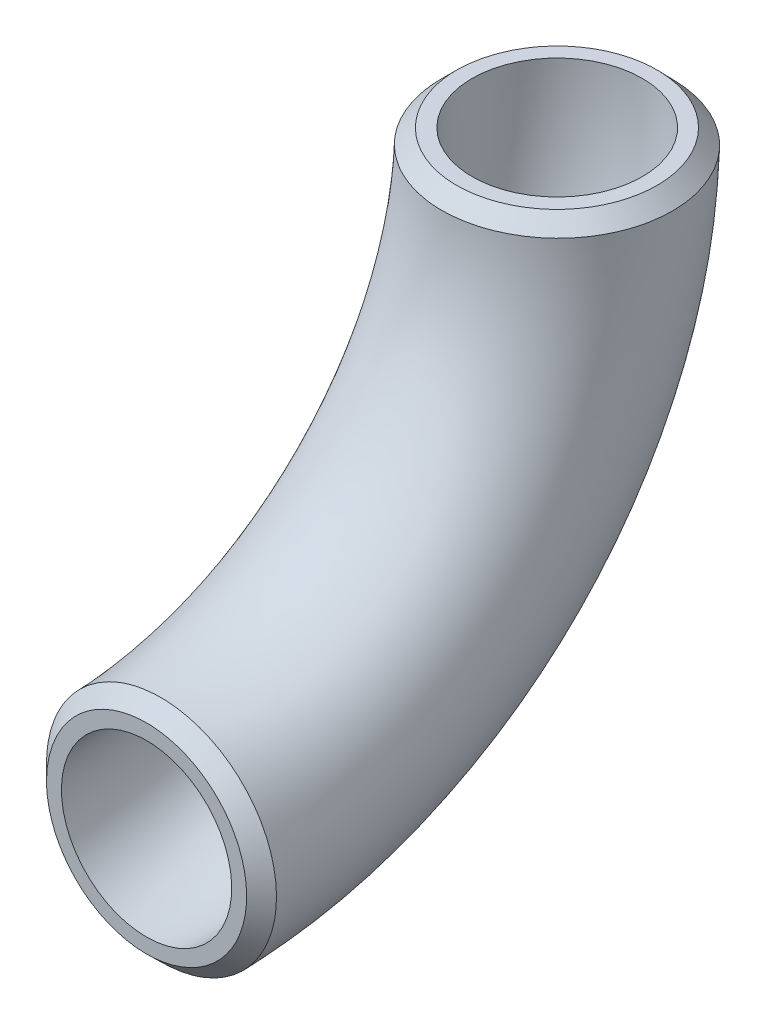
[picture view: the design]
ISO-10303-21;
HEADER;
FILE_DESCRIPTION(('STEP AP214'),'2;1');
FILE_NAME('part.step','',(''),(''),'','','');
FILE_SCHEMA(('AUTOMOTIVE_DESIGN { 1 0 10303 214 1 1 1 1 }'));
ENDSEC;
DATA;
#1=APPLICATION_CONTEXT('core data for automotive mechanical design processes');
#2=APPLICATION_PROTOCOL_DEFINITION('international standard','automotive_design',2000,#1);
#3=PRODUCT_CONTEXT('',#1,'mechanical');
#4=PRODUCT('Part','Part','',(#3));
#5=PRODUCT_RELATED_PRODUCT_CATEGORY('part','',(#4));
#6=PRODUCT_DEFINITION_FORMATION('','',#4);
#7=PRODUCT_DEFINITION_CONTEXT('part definition',#1,'design');
#8=PRODUCT_DEFINITION('design','',#6,#7);
#9=PRODUCT_DEFINITION_SHAPE('','',#8);
#10=(LENGTH_UNIT() NAMED_UNIT(*) SI_UNIT(.MILLI.,.METRE.));
#11=(NAMED_UNIT(*) PLANE_ANGLE_UNIT() SI_UNIT($,.RADIAN.));
#12=(NAMED_UNIT(*) SI_UNIT($,.STERADIAN.) SOLID_ANGLE_UNIT());
#13=UNCERTAINTY_MEASURE_WITH_UNIT(LENGTH_MEASURE(1.E-05),#10,'distance_accuracy_value','');
#14=(GEOMETRIC_REPRESENTATION_CONTEXT(3) GLOBAL_UNCERTAINTY_ASSIGNED_CONTEXT((#13)) GLOBAL_UNIT_ASSIGNED_CONTEXT((#10,
#11,#12)) REPRESENTATION_CONTEXT('',''));
#15=CARTESIAN_POINT('',(0.,0.,0.));
#16=DIRECTION('',(0.,0.,1.));
#17=DIRECTION('',(1.,0.,0.));
#18=AXIS2_PLACEMENT_3D('',#15,#16,#17);
#19=CARTESIAN_POINT('',(0.,38.1,0.));
#20=DIRECTION('',(-1.,0.,0.));
#21=DIRECTION('',(0.,0.,1.));
#22=AXIS2_PLACEMENT_3D('',#19,#20,#21);
#23=TOROIDAL_SURFACE('',#22,38.1,7.8994);
#24=CARTESIAN_POINT('',(0.,38.1,-38.1));
#25=DIRECTION('',(0.,1.,0.));
#26=DIRECTION('',(-1.,0.,0.));
#27=AXIS2_PLACEMENT_3D('',#24,#25,#26);
#28=CIRCLE('',#27,7.8994);
#29=CARTESIAN_POINT('',(0.,38.1,-45.9994));
#30=VERTEX_POINT('',#29);
#31=EDGE_CURVE('E63',#30,#30,#28,.T.);
#32=CARTESIAN_POINT('',(0.,0.,0.));
#33=DIRECTION('',(0.,0.,-1.));
#34=DIRECTION('',(-1.,0.,0.));
#35=AXIS2_PLACEMENT_3D('',#32,#33,#34);
#36=CIRCLE('',#35,7.8994);
#37=CARTESIAN_POINT('',(0.,-7.89939999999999,0.));
#38=VERTEX_POINT('',#37);
#39=EDGE_CURVE('E68',#38,#38,#36,.T.);
#40=CARTESIAN_POINT('',(0.,38.1,0.));
#41=DIRECTION('',(-1.,0.,0.));
#42=DIRECTION('',(0.,0.,1.));
#43=AXIS2_PLACEMENT_3D('',#40,#41,#42);
#44=CIRCLE('',#43,45.9994);
#45=EDGE_CURVE('',#30,#38,#44,.T.);
#46=ORIENTED_EDGE('',*,*,#31,.T.);
#47=ORIENTED_EDGE('',*,*,#39,.F.);
#48=ORIENTED_EDGE('',*,*,#45,.T.);
#49=ORIENTED_EDGE('',*,*,#45,.F.);
#50=EDGE_LOOP('',(#46,#48,#47,#49));
#51=FACE_BOUND('',#50,.T.);
#52=ADVANCED_FACE('F36',(#51),#23,.F.);
#53=CARTESIAN_POINT('',(0.,38.1,0.));
#54=DIRECTION('',(-1.,0.,0.));
#55=DIRECTION('',(0.,0.,1.));
#56=AXIS2_PLACEMENT_3D('',#53,#54,#55);
#57=TOROIDAL_SURFACE('',#56,38.1,10.668);
#58=CARTESIAN_POINT('',(-10.6679608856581,36.7155638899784,-38.1037461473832));
#59=CARTESIAN_POINT('',(-10.6712198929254,36.7221295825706,-36.7049100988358));
#60=CARTESIAN_POINT('',(-10.4015135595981,36.7293412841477,-35.3151911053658));
#61=CARTESIAN_POINT('',(-9.33458055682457,36.744176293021,-32.7239405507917));
#62=CARTESIAN_POINT('',(-8.55617914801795,36.751665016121,-31.5463033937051));
#63=CARTESIAN_POINT('',(-6.57364641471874,36.7653747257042,-29.5511046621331));
#64=CARTESIAN_POINT('',(-5.40077360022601,36.7713347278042,-28.7650983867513));
#65=CARTESIAN_POINT('',(-2.8156955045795,36.7798319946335,-27.6823186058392));
#66=CARTESIAN_POINT('',(-1.4271327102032,36.7821687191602,-27.4045568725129));
#67=CARTESIAN_POINT('',(2.7701344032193,36.7822619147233,-27.391983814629));
#68=CARTESIAN_POINT('',(5.53729471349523,36.7724846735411,-28.5309414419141));
#69=CARTESIAN_POINT('',(8.51098501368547,36.7520035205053,-31.4898224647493));
#70=CARTESIAN_POINT('',(9.30350059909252,36.7445339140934,-32.6642943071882));
#71=CARTESIAN_POINT('',(10.380604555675,36.7297030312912,-35.2493265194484));
#72=CARTESIAN_POINT('',(10.661885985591,36.7224962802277,-36.6351928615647));
#73=CARTESIAN_POINT('',(10.6739938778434,36.7092415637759,-39.4428599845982));
#74=CARTESIAN_POINT('',(10.3930080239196,36.7032472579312,-40.8531458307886));
#75=CARTESIAN_POINT('',(9.33746880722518,36.6931186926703,-43.4201557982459));
#76=CARTESIAN_POINT('',(8.54915437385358,36.6888252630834,-44.6107330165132));
#77=CARTESIAN_POINT('',(6.57653247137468,36.6820330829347,-46.5932710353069));
#78=CARTESIAN_POINT('',(5.40287707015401,36.6794966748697,-47.3853089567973));
#79=CARTESIAN_POINT('',(2.81321808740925,36.6761119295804,-48.4631194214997));
#80=CARTESIAN_POINT('',(1.42697162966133,36.6752664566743,-48.7441498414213));
#81=CARTESIAN_POINT('',(-1.37999031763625,36.6752499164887,-48.750166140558));
#82=CARTESIAN_POINT('',(-2.76843811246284,36.6760766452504,-48.4747502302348));
#83=CARTESIAN_POINT('',(-5.35894367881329,36.6794164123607,-47.4104731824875));
#84=CARTESIAN_POINT('',(-6.53759644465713,36.6819400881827,-46.6232179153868));
#85=CARTESIAN_POINT('',(-9.5100469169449,36.692052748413,-43.6629605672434));
#86=CARTESIAN_POINT('',(-10.6614428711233,36.7024325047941,-40.9014182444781));
#87=CARTESIAN_POINT('',(-10.6679608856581,36.7155638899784,-38.1037461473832));
#88=B_SPLINE_CURVE_WITH_KNOTS('',3,(#58,#59,#60,#61,#62,#63,#64,#65,#66,#67,#68,#69,#70,#71,#72,
#73,#74,#75,#76,#77,#78,#79,#80,#81,#82,#83,#84,#85,#86,#87),.UNSPECIFIED.,.T.,.F.,(4,2,2,2,2,2,
2,2,2,2,2,2,2,2,4),(-0.0570412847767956,-0.0534123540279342,-0.0497834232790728,
-0.0461544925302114,-0.04252556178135,-0.0352677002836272,-0.0316387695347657,
-0.0280098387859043,-0.0243809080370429,-0.0207519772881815,-0.0171230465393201,
-0.0134941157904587,-0.00986518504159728,-0.00623625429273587,0.00102160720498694),.UNSPECIFIED.);
#89=CARTESIAN_POINT('',(-10.6679608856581,36.7155638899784,-38.1037461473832));
#90=VERTEX_POINT('',#89);
#91=EDGE_CURVE('E48',#90,#90,#88,.F.);
#92=ORIENTED_EDGE('',*,*,#91,.T.);
#93=EDGE_LOOP('',(#92));
#94=FACE_BOUND('',#93,.T.);
#95=CARTESIAN_POINT('',(-10.6679608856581,-0.00374614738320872,-1.38443611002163));
#96=CARTESIAN_POINT('',(-10.66732328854,-0.203506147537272,-1.38537376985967));
#97=CARTESIAN_POINT('',(-10.661132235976,-0.403250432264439,-1.38629902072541));
#98=CARTESIAN_POINT('',(-10.6376664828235,-0.801713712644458,-1.38812133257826));
#99=CARTESIAN_POINT('',(-10.6204124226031,-1.00043392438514,-1.38901844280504));
#100=CARTESIAN_POINT('',(-10.5748651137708,-1.39639773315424,-1.39078368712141));
#101=CARTESIAN_POINT('',(-10.5465833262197,-1.59364264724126,-1.39165185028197));
#102=CARTESIAN_POINT('',(-10.4790357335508,-1.9862044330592,-1.39335844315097));
#103=CARTESIAN_POINT('',(-10.4397720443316,-2.18152166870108,-1.39419687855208));
#104=CARTESIAN_POINT('',(-10.350309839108,-2.5697767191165,-1.39584322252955));
#105=CARTESIAN_POINT('',(-10.3001038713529,-2.76271281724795,-1.39665110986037));
#106=CARTESIAN_POINT('',(-10.1888202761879,-3.14576047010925,-1.39823569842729));
#107=CARTESIAN_POINT('',(-10.1277253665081,-3.33586700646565,-1.39901234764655));
#108=CARTESIAN_POINT('',(-9.99467817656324,-3.7127920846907,-1.40053332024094));
#109=CARTESIAN_POINT('',(-9.92269836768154,-3.89960090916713,-1.40127755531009));
#110=CARTESIAN_POINT('',(-9.76834197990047,-4.26891332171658,-1.40273190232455));
#111=CARTESIAN_POINT('',(-9.68596330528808,-4.45141603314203,-1.40344200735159));
#112=CARTESIAN_POINT('',(-9.51138206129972,-4.8111504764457,-1.40482708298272));
#113=CARTESIAN_POINT('',(-9.41920213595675,-4.98839319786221,-1.40550212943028));
#114=CARTESIAN_POINT('',(-9.22521964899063,-5.3372123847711,-1.406816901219));
#115=CARTESIAN_POINT('',(-9.12343059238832,-5.50879635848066,-1.40745667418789));
#116=CARTESIAN_POINT('',(-8.91047883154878,-5.8459247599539,-1.40870120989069));
#117=CARTESIAN_POINT('',(-8.79932087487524,-6.01147218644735,-1.40930599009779));
#118=CARTESIAN_POINT('',(-8.56786754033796,-6.3361501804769,-1.41048070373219));
#119=CARTESIAN_POINT('',(-8.44756859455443,-6.49527820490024,-1.4110506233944));
#120=CARTESIAN_POINT('',(-8.19806998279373,-6.8067400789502,-1.41215587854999));
#121=CARTESIAN_POINT('',(-8.06885883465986,-6.95906473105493,-1.41269116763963));
#122=CARTESIAN_POINT('',(-7.80178062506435,-7.25655270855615,-1.41372718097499));
#123=CARTESIAN_POINT('',(-7.66389458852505,-7.40169900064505,-1.41422782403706));
#124=CARTESIAN_POINT('',(-7.38011740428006,-7.68398961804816,-1.41519394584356));
#125=CARTESIAN_POINT('',(-7.23422501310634,-7.82113269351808,-1.41565941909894));
#126=CARTESIAN_POINT('',(-6.9352305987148,-8.08667535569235,-1.41655459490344));
#127=CARTESIAN_POINT('',(-6.78214414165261,-8.21509247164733,-1.41698436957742));
#128=CARTESIAN_POINT('',(-6.46920580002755,-8.4629592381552,-1.41780835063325));
#129=CARTESIAN_POINT('',(-6.30936311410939,-8.58242050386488,-1.41820260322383));
#130=CARTESIAN_POINT('',(-5.98334548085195,-8.81214052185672,-1.41895597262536));
#131=CARTESIAN_POINT('',(-5.81717452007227,-8.92240493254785,-1.41931511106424));
#132=CARTESIAN_POINT('',(-5.47893671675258,-9.13350324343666,-1.41999862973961));
#133=CARTESIAN_POINT('',(-5.30686961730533,-9.23433673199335,-1.42032300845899));
#134=CARTESIAN_POINT('',(-4.95726732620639,-9.426328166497,-1.42093736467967));
#135=CARTESIAN_POINT('',(-4.77972846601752,-9.51747943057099,-1.42122731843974));
#136=CARTESIAN_POINT('',(-4.4196358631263,-9.68992299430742,-1.42177331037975));
#137=CARTESIAN_POINT('',(-4.2370758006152,-9.77120210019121,-1.42202930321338));
#138=CARTESIAN_POINT('',(-3.86765060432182,-9.92334300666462,-1.42250689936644));
#139=CARTESIAN_POINT('',(-3.68078526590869,-9.99420431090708,-1.42272850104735));
#140=CARTESIAN_POINT('',(-3.30355822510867,-10.1250795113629,-1.42313658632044));
#141=CARTESIAN_POINT('',(-3.11320122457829,-10.1851069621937,-1.42332311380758));
#142=CARTESIAN_POINT('',(-2.72955402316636,-10.2943012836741,-1.42366141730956));
#143=CARTESIAN_POINT('',(-2.53626613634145,-10.3434762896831,-1.42381321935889));
#144=CARTESIAN_POINT('',(-2.1472952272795,-10.430887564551,-1.42408229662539));
#145=CARTESIAN_POINT('',(-1.95161295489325,-10.4691271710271,-1.42419958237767));
#146=CARTESIAN_POINT('',(-1.55839708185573,-10.5346128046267,-1.42439989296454));
#147=CARTESIAN_POINT('',(-1.36086329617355,-10.561857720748,-1.42448291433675));
#148=CARTESIAN_POINT('',(-0.964485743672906,-10.6052672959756,-1.42461492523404));
#149=CARTESIAN_POINT('',(-0.765641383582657,-10.6214265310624,-1.42466389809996));
#150=CARTESIAN_POINT('',(-0.367184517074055,-10.6426799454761,-1.42472813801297));
#151=CARTESIAN_POINT('',(-0.16757148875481,-10.6477643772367,-1.42474337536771));
#152=CARTESIAN_POINT('',(0.231601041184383,-10.6465072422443,-1.42474011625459));
#153=CARTESIAN_POINT('',(0.431160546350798,-10.6401670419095,-1.42472162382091));
#154=CARTESIAN_POINT('',(0.829374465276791,-10.6159637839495,-1.42465046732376));
#155=CARTESIAN_POINT('',(1.02802959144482,-10.598112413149,-1.42459783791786));
#156=CARTESIAN_POINT('',(1.42388728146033,-10.5511983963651,-1.42445841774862));
#157=CARTESIAN_POINT('',(1.62109064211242,-10.5221424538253,-1.42437164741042));
#158=CARTESIAN_POINT('',(2.01349497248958,-10.4530278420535,-1.42416385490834));
#159=CARTESIAN_POINT('',(2.20869654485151,-10.4129725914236,-1.42404284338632));
#160=CARTESIAN_POINT('',(2.59654839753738,-10.3220933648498,-1.4237664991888));
#161=CARTESIAN_POINT('',(2.78919899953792,-10.2712707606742,-1.42361117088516));
#162=CARTESIAN_POINT('',(3.17139981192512,-10.1590823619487,-1.4232661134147));
#163=CARTESIAN_POINT('',(3.36095008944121,-10.097716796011,-1.4230763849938));
#164=CARTESIAN_POINT('',(3.73640112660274,-9.9646690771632,-1.42266244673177));
#165=CARTESIAN_POINT('',(3.92230176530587,-9.8929865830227,-1.42243823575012));
#166=CARTESIAN_POINT('',(4.28990424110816,-9.73953050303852,-1.42195524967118));
#167=CARTESIAN_POINT('',(4.47160581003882,-9.65775627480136,-1.42169647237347));
#168=CARTESIAN_POINT('',(4.83026091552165,-9.48434222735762,-1.421144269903));
#169=CARTESIAN_POINT('',(5.00721399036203,-9.39270145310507,-1.42085084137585));
#170=CARTESIAN_POINT('',(5.35582246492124,-9.19977933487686,-1.42022925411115));
#171=CARTESIAN_POINT('',(5.52747701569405,-9.09849645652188,-1.41990108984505));
#172=CARTESIAN_POINT('',(5.86494064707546,-8.88651714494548,-1.41920994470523));
#173=CARTESIAN_POINT('',(6.03074808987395,-8.77581810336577,-1.41884695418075));
#174=CARTESIAN_POINT('',(6.35596394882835,-8.54522756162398,-1.41808609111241));
#175=CARTESIAN_POINT('',(6.51536926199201,-8.42533168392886,-1.41768820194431));
#176=CARTESIAN_POINT('',(6.82725106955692,-8.17659318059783,-1.41685740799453));
#177=CARTESIAN_POINT('',(6.97972199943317,-8.0477435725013,-1.41642447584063));
#178=CARTESIAN_POINT('',(7.27712012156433,-7.78125475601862,-1.41552373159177));
#179=CARTESIAN_POINT('',(7.42203778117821,-7.64360490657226,-1.41505587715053));
#180=CARTESIAN_POINT('',(7.70374376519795,-7.36030392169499,-1.4140854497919));
#181=CARTESIAN_POINT('',(7.84053414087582,-7.21465482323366,-1.41358288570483));
#182=CARTESIAN_POINT('',(8.1056210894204,-6.91625520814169,-1.41254290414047));
#183=CARTESIAN_POINT('',(8.23393133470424,-6.76351683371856,-1.41200554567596));
#184=CARTESIAN_POINT('',(8.48169476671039,-6.45124554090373,-1.41089598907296));
#185=CARTESIAN_POINT('',(8.60115604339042,-6.29171904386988,-1.4103238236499));
#186=CARTESIAN_POINT('',(8.83094898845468,-5.96626470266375,-1.40914438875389));
#187=CARTESIAN_POINT('',(8.94128232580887,-5.80033803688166,-1.40853712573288));
#188=CARTESIAN_POINT('',(9.15252017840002,-5.46245129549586,-1.40728731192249));
#189=CARTESIAN_POINT('',(9.25341911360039,-5.29048773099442,-1.40664474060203));
#190=CARTESIAN_POINT('',(9.44550934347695,-4.94090640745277,-1.40532408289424));
#191=CARTESIAN_POINT('',(9.53668684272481,-4.76328106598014,-1.40464594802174));
#192=CARTESIAN_POINT('',(9.7090053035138,-4.40273199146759,-1.40325403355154));
#193=CARTESIAN_POINT('',(9.79012302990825,-4.2197971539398,-1.40254017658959));
#194=CARTESIAN_POINT('',(9.94192654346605,-3.84968028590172,-1.40107877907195));
#195=CARTESIAN_POINT('',(10.0126136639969,-3.66249880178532,-1.40033124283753));
#196=CARTESIAN_POINT('',(10.1433015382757,-3.28494678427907,-1.39880472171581));
#197=CARTESIAN_POINT('',(10.2033276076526,-3.09458501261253,-1.39802581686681));
#198=CARTESIAN_POINT('',(10.3125797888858,-2.7110573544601,-1.39643691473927));
#199=CARTESIAN_POINT('',(10.3618200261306,-2.51789549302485,-1.39562695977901));
#200=CARTESIAN_POINT('',(10.4494353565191,-2.12917082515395,-1.39397620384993));
#201=CARTESIAN_POINT('',(10.4878129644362,-1.93360858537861,-1.3931354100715));
#202=CARTESIAN_POINT('',(10.5536323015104,-1.54047983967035,-1.39142327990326));
#203=CARTESIAN_POINT('',(10.5810646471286,-1.34291176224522,-1.39055191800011));
#204=CARTESIAN_POINT('',(10.6248983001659,-0.94616786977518,-1.38877882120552));
#205=CARTESIAN_POINT('',(10.6412780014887,-0.746989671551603,-1.38787703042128));
#206=CARTESIAN_POINT('',(10.6630161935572,-0.347421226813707,-1.38604370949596));
#207=CARTESIAN_POINT('',(10.6683408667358,-0.147029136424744,-1.3851120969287));
#208=CARTESIAN_POINT('',(10.6675839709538,0.254109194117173,-1.38322022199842));
#209=CARTESIAN_POINT('',(10.6614813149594,0.454855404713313,-1.38225990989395));
#210=CARTESIAN_POINT('',(10.6377444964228,0.855602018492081,-1.38031473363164));
#211=CARTESIAN_POINT('',(10.620113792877,1.0556026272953,-1.37932987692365));
#212=CARTESIAN_POINT('',(10.5736326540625,1.45414029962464,-1.37733973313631));
#213=CARTESIAN_POINT('',(10.5447906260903,1.65267834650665,-1.37633446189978));
#214=CARTESIAN_POINT('',(10.4760905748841,2.04756967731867,-1.37430716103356));
#215=CARTESIAN_POINT('',(10.4362470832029,2.24392549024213,-1.37328515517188));
#216=CARTESIAN_POINT('',(10.3457748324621,2.63373095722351,-1.37122817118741));
#217=CARTESIAN_POINT('',(10.2951673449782,2.82718554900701,-1.37019322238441));
#218=CARTESIAN_POINT('',(10.1833911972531,3.21046629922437,-1.36811413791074));
#219=CARTESIAN_POINT('',(10.1222507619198,3.40030068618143,-1.367070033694));
#220=CARTESIAN_POINT('',(9.98962850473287,3.77561696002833,-1.36497632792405));
#221=CARTESIAN_POINT('',(9.91818166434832,3.96111119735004,-1.36392675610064));
#222=CARTESIAN_POINT('',(9.76494798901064,4.32760160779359,-1.36182290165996));
#223=CARTESIAN_POINT('',(9.68316958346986,4.50860130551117,-1.36076862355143));
#224=CARTESIAN_POINT('',(9.50945665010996,4.86609248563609,-1.35865784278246));
#225=CARTESIAN_POINT('',(9.41750264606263,5.0425744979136,-1.35760133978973));
#226=CARTESIAN_POINT('',(9.22376797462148,5.39043523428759,-1.35549134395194));
#227=CARTESIAN_POINT('',(9.1219715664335,5.56180519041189,-1.35443785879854));
#228=CARTESIAN_POINT('',(8.90888826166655,5.89884823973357,-1.35233925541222));
#229=CARTESIAN_POINT('',(8.79758932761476,6.06451372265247,-1.35129414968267));
#230=CARTESIAN_POINT('',(8.56583164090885,6.38954966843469,-1.34921759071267));
#231=CARTESIAN_POINT('',(8.44536418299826,6.54891392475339,-1.34818615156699));
#232=CARTESIAN_POINT('',(8.19561572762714,6.86076329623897,-1.34614239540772));
#233=CARTESIAN_POINT('',(8.06632872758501,7.01324360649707,-1.34513009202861));
#234=CARTESIAN_POINT('',(7.79923262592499,7.31068784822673,-1.34312942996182));
#235=CARTESIAN_POINT('',(7.66141931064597,7.45564799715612,-1.34214108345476));
#236=CARTESIAN_POINT('',(7.37796902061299,7.73741528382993,-1.34019694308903));
#237=CARTESIAN_POINT('',(7.23233982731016,7.87423025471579,-1.33924111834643));
#238=CARTESIAN_POINT('',(6.93398430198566,8.13932099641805,-1.33737076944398));
#239=CARTESIAN_POINT('',(6.78127145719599,8.26761194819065,-1.33645617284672));
#240=CARTESIAN_POINT('',(6.46905879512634,8.51533151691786,-1.33467286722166));
#241=CARTESIAN_POINT('',(6.30956571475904,8.63476862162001,-1.33380411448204));
#242=CARTESIAN_POINT('',(5.98415583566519,8.86451382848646,-1.33211771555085));
#243=CARTESIAN_POINT('',(5.81823962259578,8.9748227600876,-1.33130006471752));
#244=CARTESIAN_POINT('',(5.48033051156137,9.18602824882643,-1.3297208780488));
#245=CARTESIAN_POINT('',(5.30833273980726,9.28691700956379,-1.32895938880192));
#246=CARTESIAN_POINT('',(4.95861528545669,9.47901447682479,-1.32749767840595));
#247=CARTESIAN_POINT('',(4.78088599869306,9.57020570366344,-1.32679756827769));
#248=CARTESIAN_POINT('',(4.42004122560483,9.74259996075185,-1.32546332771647));
#249=CARTESIAN_POINT('',(4.23691215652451,9.82377456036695,-1.32482938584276));
#250=CARTESIAN_POINT('',(3.86633633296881,9.97570633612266,-1.32363589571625));
#251=CARTESIAN_POINT('',(3.67888859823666,10.0464611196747,-1.32307636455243));
#252=CARTESIAN_POINT('',(3.30079522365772,10.1772433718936,-1.32203792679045));
#253=CARTESIAN_POINT('',(3.1101584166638,10.2372963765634,-1.3215588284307));
#254=CARTESIAN_POINT('',(2.72611675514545,10.3465556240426,-1.32068327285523));
#255=CARTESIAN_POINT('',(2.53271660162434,10.3957783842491,-1.32028668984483));
#256=CARTESIAN_POINT('',(2.14359303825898,10.4832985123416,-1.31957859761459));
#257=CARTESIAN_POINT('',(1.94787123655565,10.5216030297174,-1.31926703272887));
#258=CARTESIAN_POINT('',(1.55454381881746,10.5871992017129,-1.31873127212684));
#259=CARTESIAN_POINT('',(1.3569377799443,10.6144883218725,-1.31850709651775));
#260=CARTESIAN_POINT('',(0.960281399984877,10.6579623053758,-1.31814851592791));
#261=CARTESIAN_POINT('',(0.761229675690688,10.6741345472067,-1.31801421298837));
#262=CARTESIAN_POINT('',(0.362120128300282,10.6953096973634,-1.31783745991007));
#263=CARTESIAN_POINT('',(0.162061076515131,10.7002894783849,-1.31779519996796));
#264=CARTESIAN_POINT('',(-0.238064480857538,10.6989171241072,-1.31780573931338));
#265=CARTESIAN_POINT('',(-0.438130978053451,10.6925624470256,-1.317858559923));
#266=CARTESIAN_POINT('',(-0.837224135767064,10.6685390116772,-1.31805762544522));
#267=CARTESIAN_POINT('',(-1.03625201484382,10.6508904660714,-1.31820370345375));
#268=CARTESIAN_POINT('',(-1.43276991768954,10.6044569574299,-1.31858600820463));
#269=CARTESIAN_POINT('',(-1.63026145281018,10.5756848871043,-1.31882213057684));
#270=CARTESIAN_POINT('',(-2.02320808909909,10.50715281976,-1.31938155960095));
#271=CARTESIAN_POINT('',(-2.21866431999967,10.4673992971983,-1.31970481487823));
#272=CARTESIAN_POINT('',(-2.60704442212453,10.377063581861,-1.32043549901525));
#273=CARTESIAN_POINT('',(-2.79996845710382,10.3264820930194,-1.32084292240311));
#274=CARTESIAN_POINT('',(-3.1827819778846,10.2146305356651,-1.32173886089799));
#275=CARTESIAN_POINT('',(-3.37267011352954,10.1533558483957,-1.32222741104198));
#276=CARTESIAN_POINT('',(-3.74893535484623,10.020319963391,-1.32328289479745));
#277=CARTESIAN_POINT('',(-3.93530905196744,9.94854912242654,-1.32384990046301));
#278=CARTESIAN_POINT('',(-4.3037181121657,9.79459874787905,-1.32505735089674));
#279=CARTESIAN_POINT('',(-4.48575333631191,9.71241888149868,-1.32569779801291));
#280=CARTESIAN_POINT('',(-4.84468633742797,9.53790045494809,-1.32704504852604));
#281=CARTESIAN_POINT('',(-5.02158852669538,9.44557096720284,-1.3277517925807));
#282=CARTESIAN_POINT('',(-5.36982498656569,9.25115361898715,-1.32922663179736));
#283=CARTESIAN_POINT('',(-5.54116207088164,9.14907079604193,-1.32999469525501));
#284=CARTESIAN_POINT('',(-5.87780931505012,8.93548346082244,-1.33158676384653));
#285=CARTESIAN_POINT('',(-6.0431206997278,8.82398087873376,-1.33241075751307));
#286=CARTESIAN_POINT('',(-6.36726937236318,8.59191083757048,-1.33410950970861));
#287=CARTESIAN_POINT('',(-6.52610623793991,8.47134278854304,-1.33498427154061));
#288=CARTESIAN_POINT('',(-6.83683968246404,8.22147650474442,-1.33677890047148));
#289=CARTESIAN_POINT('',(-6.98873403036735,8.09217549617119,-1.33769878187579));
#290=CARTESIAN_POINT('',(-7.28518068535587,7.82524291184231,-1.33957972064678));
#291=CARTESIAN_POINT('',(-7.42972866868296,7.68760653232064,-1.34054080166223));
#292=CARTESIAN_POINT('',(-7.71068298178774,7.4043241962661,-1.34249267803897));
#293=CARTESIAN_POINT('',(-7.84709141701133,7.25868032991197,-1.34348346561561));
#294=CARTESIAN_POINT('',(-8.1111541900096,6.95990551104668,-1.34548459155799));
#295=CARTESIAN_POINT('',(-8.23881652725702,6.80678162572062,-1.3464949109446));
#296=CARTESIAN_POINT('',(-8.48521236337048,6.49364564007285,-1.34853255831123));
#297=CARTESIAN_POINT('',(-8.60395050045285,6.33363718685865,-1.34955987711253));
#298=CARTESIAN_POINT('',(-8.83225614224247,6.00726718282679,-1.35162725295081));
#299=CARTESIAN_POINT('',(-8.94182590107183,5.84090720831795,-1.35266730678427));
#300=CARTESIAN_POINT('',(-9.15156966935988,5.50238468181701,-1.35475635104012));
#301=CARTESIAN_POINT('',(-9.25174434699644,5.3302225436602,-1.35580534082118));
#302=CARTESIAN_POINT('',(-9.4424672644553,4.98064092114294,-1.35790833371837));
#303=CARTESIAN_POINT('',(-9.53301522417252,4.80322128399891,-1.35896233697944));
#304=CARTESIAN_POINT('',(-9.70425461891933,4.44367054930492,-1.36107146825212));
#305=CARTESIAN_POINT('',(-9.78494525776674,4.26153907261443,-1.36212659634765));
#306=CARTESIAN_POINT('',(-9.93623913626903,3.89310993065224,-1.36423408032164));
#307=CARTESIAN_POINT('',(-10.0068412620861,3.70681180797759,-1.36528643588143));
#308=CARTESIAN_POINT('',(-10.1377271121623,3.33059460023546,-1.36738448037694));
#309=CARTESIAN_POINT('',(-10.1980093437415,3.14067499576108,-1.36843016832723));
#310=CARTESIAN_POINT('',(-10.308024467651,2.75776006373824,-1.37051098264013));
#311=CARTESIAN_POINT('',(-10.3577551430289,2.56476409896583,-1.3715461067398));
#312=CARTESIAN_POINT('',(-10.4464364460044,2.17624160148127,-1.37360189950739));
#313=CARTESIAN_POINT('',(-10.4853834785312,1.98071424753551,-1.37462256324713));
#314=CARTESIAN_POINT('',(-10.5522679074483,1.58767472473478,-1.37664554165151));
#315=CARTESIAN_POINT('',(-10.58019934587,1.39016154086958,-1.37764784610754));
#316=CARTESIAN_POINT('',(-10.6248222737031,0.993694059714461,-1.37963021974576));
#317=CARTESIAN_POINT('',(-10.6415041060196,0.794738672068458,-1.38061026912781));
#318=CARTESIAN_POINT('',(-10.6634052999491,0.395937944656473,-1.38254423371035));
#319=CARTESIAN_POINT('',(-10.6686096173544,0.196091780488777,-1.38349811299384));
#320=CARTESIAN_POINT('',(-10.6679608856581,-0.00374614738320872,-1.38443611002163));
#321=B_SPLINE_CURVE_WITH_KNOTS('',3,(#95,#96,#97,#98,#99,#100,#101,#102,#103,#104,#105,#106,
#107,#108,#109,#110,#111,#112,#113,#114,#115,#116,#117,#118,#119,#120,#121,#122,#123,#124,#125,
#126,#127,#128,#129,#130,#131,#132,#133,#134,#135,#136,#137,#138,#139,#140,#141,#142,#143,#144,
#145,#146,#147,#148,#149,#150,#151,#152,#153,#154,#155,#156,#157,#158,#159,#160,#161,#162,#163,
#164,#165,#166,#167,#168,#169,#170,#171,#172,#173,#174,#175,#176,#177,#178,#179,#180,#181,#182,
#183,#184,#185,#186,#187,#188,#189,#190,#191,#192,#193,#194,#195,#196,#197,#198,#199,#200,#201,
#202,#203,#204,#205,#206,#207,#208,#209,#210,#211,#212,#213,#214,#215,#216,#217,#218,#219,#220,
#221,#222,#223,#224,#225,#226,#227,#228,#229,#230,#231,#232,#233,#234,#235,#236,#237,#238,#239,
#240,#241,#242,#243,#244,#245,#246,#247,#248,#249,#250,#251,#252,#253,#254,#255,#256,#257,#258,
#259,#260,#261,#262,#263,#264,#265,#266,#267,#268,#269,#270,#271,#272,#273,#274,#275,#276,#277,
#278,#279,#280,#281,#282,#283,#284,#285,#286,#287,#288,#289,#290,#291,#292,#293,#294,#295,#296,
#297,#298,#299,#300,#301,#302,#303,#304,#305,#306,#307,#308,#309,#310,#311,#312,#313,#314,#315,
#316,#317,#318,#319,#320),.UNSPECIFIED.,.F.,.F.,(4,2,2,2,2,2,2,2,2,2,2,2,2,2,2,2,2,2,2,2,2,2,2,
2,2,2,2,2,2,2,2,2,2,2,2,2,2,2,2,2,2,2,2,2,2,2,2,2,2,2,2,2,2,2,2,2,2,2,2,2,2,2,2,2,2,2,2,2,2,2,2,
2,2,2,2,2,2,2,2,2,2,2,2,2,2,2,2,2,2,2,2,2,2,2,2,2,2,2,2,2,2,2,2,2,2,2,2,2,2,2,2,2,4),(0.,
0.599215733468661,1.1973167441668,1.79479780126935,2.39216382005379,2.98993792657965,
3.58866937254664,4.1889411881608,4.78933417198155,5.38836901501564,5.98657414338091,
6.58447794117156,7.18261632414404,7.78154026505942,8.38182316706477,8.98219956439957,
9.58133187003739,10.1796731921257,10.7776436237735,11.3756401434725,11.9740467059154,
12.5732444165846,13.1724706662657,13.7709419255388,14.3689630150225,14.9668013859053,
15.5647001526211,16.1628912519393,16.76160864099,17.3602544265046,17.9582933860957,
18.5559751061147,19.1534712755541,19.7508913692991,20.3482985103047,20.9457254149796,
21.5431903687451,22.1407132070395,22.738331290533,23.3361154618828,23.9341859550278,
24.5327281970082,25.1320083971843,25.7311366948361,26.3292741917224,26.926857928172,
27.5243321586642,28.1221575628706,28.7208203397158,29.3208410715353,29.9207850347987,
30.519284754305,31.1169959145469,31.7145685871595,32.3126524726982,32.9119021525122,
33.5129822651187,34.1151726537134,34.7171824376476,35.3187416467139,35.9195100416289,
36.5191020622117,37.1171116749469,37.7131373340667,38.3086798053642,38.9053825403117,
39.5030558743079,40.1014978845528,40.7005153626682,41.299944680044,41.8996726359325,
42.4988141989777,43.0968584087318,43.6943216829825,44.2917306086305,44.8896296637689,
45.4885887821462,46.089210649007,46.6899702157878,47.2892765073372,47.8876623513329,
48.4856554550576,49.0837860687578,49.6825946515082,50.2826394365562,50.8828188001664,
51.4819270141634,52.0803429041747,52.6784067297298,53.2764316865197,53.8747155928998,
54.4735526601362,55.0724088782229,55.6707340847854,56.268751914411,56.8666475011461,
57.4645820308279,58.0627073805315,58.6611807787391,59.2594986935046,59.8572618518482,
60.4547121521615,61.0520151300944,61.6492755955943,62.246553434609,62.843879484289,
63.4412714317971,64.0387497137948,64.6363534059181,65.2341560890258,65.8322816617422,
66.4309200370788,67.0303426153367),.UNSPECIFIED.);
#322=CARTESIAN_POINT('',(-10.6679608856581,-0.00374614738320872,-1.38443611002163));
#323=VERTEX_POINT('',#322);
#324=EDGE_CURVE('E53',#323,#323,#321,.F.);
#325=ORIENTED_EDGE('',*,*,#324,.T.);
#326=EDGE_LOOP('',(#325));
#327=FACE_BOUND('',#326,.T.);
#328=ADVANCED_FACE('F90',(#94,#327),#57,.T.);
#329=CARTESIAN_POINT('',(0.,38.1,-38.1));
#330=DIRECTION('',(0.,1.,0.));
#331=DIRECTION('',(-1.,0.,0.));
#332=AXIS2_PLACEMENT_3D('',#329,#330,#331);
#333=PLANE('',#332);
#334=CARTESIAN_POINT('',(-9.28366596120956,38.1,-38.1));
#335=CARTESIAN_POINT('',(-9.28326468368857,38.1,-38.2738063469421));
#336=CARTESIAN_POINT('',(-9.2777801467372,38.1,-38.4475916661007));
#337=CARTESIAN_POINT('',(-9.25683286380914,38.1,-38.7943622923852));
#338=CARTESIAN_POINT('',(-9.24138150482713,38.1,-38.9673482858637));
#339=CARTESIAN_POINT('',(-9.20070164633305,38.1,-39.3120385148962));
#340=CARTESIAN_POINT('',(-9.1754801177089,38.1,-39.4837435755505));
#341=CARTESIAN_POINT('',(-9.11546451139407,38.1,-39.825397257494));
#342=CARTESIAN_POINT('',(-9.0806744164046,38.1,-39.9953465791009));
#343=CARTESIAN_POINT('',(-9.00172345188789,38.1,-40.3330124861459));
#344=CARTESIAN_POINT('',(-8.95756469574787,38.1,-40.5007295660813));
#345=CARTESIAN_POINT('',(-8.86007746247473,38.1,-40.8334551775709));
#346=CARTESIAN_POINT('',(-8.80675004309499,38.1,-40.9984640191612));
#347=CARTESIAN_POINT('',(-8.69112564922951,38.1,-41.3252971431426));
#348=CARTESIAN_POINT('',(-8.62882920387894,38.1,-41.4871216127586));
#349=CARTESIAN_POINT('',(-8.49546641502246,38.1,-41.8071098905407));
#350=CARTESIAN_POINT('',(-8.42440033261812,38.1,-41.9652738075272));
#351=CARTESIAN_POINT('',(-8.2736977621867,38.1,-42.277464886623));
#352=CARTESIAN_POINT('',(-8.1940612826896,38.1,-42.4314920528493));
#353=CARTESIAN_POINT('',(-8.02641705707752,38.1,-42.7349332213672));
#354=CARTESIAN_POINT('',(-7.93840885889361,38.1,-42.8843469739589));
#355=CARTESIAN_POINT('',(-7.75422183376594,38.1,-43.1780862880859));
#356=CARTESIAN_POINT('',(-7.65804168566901,38.1,-43.3224110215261));
#357=CARTESIAN_POINT('',(-7.45770698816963,38.1,-43.6054929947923));
#358=CARTESIAN_POINT('',(-7.35354966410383,38.1,-43.7442482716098));
#359=CARTESIAN_POINT('',(-7.13747540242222,38.1,-44.0157298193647));
#360=CARTESIAN_POINT('',(-7.02555352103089,38.1,-44.1484521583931));
#361=CARTESIAN_POINT('',(-6.7940984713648,38.1,-44.4073428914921));
#362=CARTESIAN_POINT('',(-6.67455730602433,38.1,-44.5335041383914));
#363=CARTESIAN_POINT('',(-6.4284642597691,38.1,-44.7787896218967));
#364=CARTESIAN_POINT('',(-6.30191223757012,38.1,-44.8979137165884));
#365=CARTESIAN_POINT('',(-6.04252937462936,38.1,-45.1288236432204));
#366=CARTESIAN_POINT('',(-5.90970547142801,38.1,-45.2406172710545));
#367=CARTESIAN_POINT('',(-5.6380920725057,38.1,-45.456534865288));
#368=CARTESIAN_POINT('',(-5.49930621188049,38.1,-45.5606634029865));
#369=CARTESIAN_POINT('',(-5.21614711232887,38.1,-45.7609871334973));
#370=CARTESIAN_POINT('',(-5.07177453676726,38.1,-45.8571832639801));
#371=CARTESIAN_POINT('',(-4.77780082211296,38.1,-46.0413573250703));
#372=CARTESIAN_POINT('',(-4.62819768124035,38.1,-46.1293320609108));
#373=CARTESIAN_POINT('',(-4.32413203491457,38.1,-46.2967976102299));
#374=CARTESIAN_POINT('',(-4.16966512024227,38.1,-46.3762804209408));
#375=CARTESIAN_POINT('',(-3.85621709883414,38.1,-46.5264439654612));
#376=CARTESIAN_POINT('',(-3.69722939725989,38.1,-46.597110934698));
#377=CARTESIAN_POINT('',(-3.37553391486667,38.1,-46.7293698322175));
#378=CARTESIAN_POINT('',(-3.2128262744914,38.1,-46.7909621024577));
#379=CARTESIAN_POINT('',(-2.88450360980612,38.1,-46.9049307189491));
#380=CARTESIAN_POINT('',(-2.71889358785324,38.1,-46.9573214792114));
#381=CARTESIAN_POINT('',(-2.38514911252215,38.1,-47.0527419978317));
#382=CARTESIAN_POINT('',(-2.21701691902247,38.1,-47.0957796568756));
#383=CARTESIAN_POINT('',(-1.87863113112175,38.1,-47.1724017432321));
#384=CARTESIAN_POINT('',(-1.70837776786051,38.1,-47.2059871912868));
#385=CARTESIAN_POINT('',(-1.36614634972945,38.1,-47.2635986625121));
#386=CARTESIAN_POINT('',(-1.19416724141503,38.1,-47.287618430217));
#387=CARTESIAN_POINT('',(-0.848881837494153,38.1,-47.325997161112));
#388=CARTESIAN_POINT('',(-0.675573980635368,38.1,-47.3403420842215));
#389=CARTESIAN_POINT('',(-0.328027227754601,38.1,-47.3592667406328));
#390=CARTESIAN_POINT('',(-0.153787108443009,38.1,-47.3638240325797));
#391=CARTESIAN_POINT('',(0.194657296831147,38.1,-47.3630804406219));
#392=CARTESIAN_POINT('',(0.368861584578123,38.1,-47.3577803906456));
#393=CARTESIAN_POINT('',(0.716278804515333,38.1,-47.3373779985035));
#394=CARTESIAN_POINT('',(0.889493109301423,38.1,-47.3222990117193));
#395=CARTESIAN_POINT('',(1.23455362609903,38.1,-47.2824492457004));
#396=CARTESIAN_POINT('',(1.40640143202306,38.1,-47.257692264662));
#397=CARTESIAN_POINT('',(1.7483527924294,38.1,-47.1985978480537));
#398=CARTESIAN_POINT('',(1.91845717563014,38.1,-47.16426520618));
#399=CARTESIAN_POINT('',(2.25654793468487,38.1,-47.0861331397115));
#400=CARTESIAN_POINT('',(2.42453345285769,38.1,-47.0423300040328));
#401=CARTESIAN_POINT('',(2.75800829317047,38.1,-46.9453569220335));
#402=CARTESIAN_POINT('',(2.92349418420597,38.1,-46.8921751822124));
#403=CARTESIAN_POINT('',(3.25161231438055,38.1,-46.776594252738));
#404=CARTESIAN_POINT('',(3.41423771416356,38.1,-46.7141756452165));
#405=CARTESIAN_POINT('',(3.7357218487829,38.1,-46.5802839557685));
#406=CARTESIAN_POINT('',(3.89458057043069,38.1,-46.5088108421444));
#407=CARTESIAN_POINT('',(4.20763164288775,38.1,-46.3570919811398));
#408=CARTESIAN_POINT('',(4.36183326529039,38.1,-46.2768653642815));
#409=CARTESIAN_POINT('',(4.66525445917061,38.1,-46.1079599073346));
#410=CARTESIAN_POINT('',(4.81448063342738,38.1,-46.019292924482));
#411=CARTESIAN_POINT('',(5.10761330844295,38.1,-45.8337758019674));
#412=CARTESIAN_POINT('',(5.25152337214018,38.1,-45.7369312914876));
#413=CARTESIAN_POINT('',(5.53369523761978,38.1,-45.5353433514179));
#414=CARTESIAN_POINT('',(5.67195716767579,38.1,-45.4306001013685));
#415=CARTESIAN_POINT('',(5.94249214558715,38.1,-45.2134836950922));
#416=CARTESIAN_POINT('',(6.07476147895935,38.1,-45.1011059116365));
#417=CARTESIAN_POINT('',(6.33301191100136,38.1,-44.8690304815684));
#418=CARTESIAN_POINT('',(6.4589850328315,38.1,-44.7493239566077));
#419=CARTESIAN_POINT('',(6.70408068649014,38.1,-44.5028606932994));
#420=CARTESIAN_POINT('',(6.82319657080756,38.1,-44.3760973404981));
#421=CARTESIAN_POINT('',(7.05405182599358,38.1,-44.1160098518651));
#422=CARTESIAN_POINT('',(7.16579069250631,38.1,-43.982685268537));
#423=CARTESIAN_POINT('',(7.38160623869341,38.1,-43.710043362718));
#424=CARTESIAN_POINT('',(7.48568531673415,38.1,-43.5707279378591));
#425=CARTESIAN_POINT('',(7.68585245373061,38.1,-43.2866325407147));
#426=CARTESIAN_POINT('',(7.78194666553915,38.1,-43.1418569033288));
#427=CARTESIAN_POINT('',(7.96582570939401,38.1,-42.8473797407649));
#428=CARTESIAN_POINT('',(8.05362105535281,38.1,-42.6976847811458));
#429=CARTESIAN_POINT('',(8.22058002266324,38.1,-42.3939053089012));
#430=CARTESIAN_POINT('',(8.29975886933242,38.1,-42.2398291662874));
#431=CARTESIAN_POINT('',(8.4491641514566,38.1,-41.9278237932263));
#432=CARTESIAN_POINT('',(8.51941056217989,38.1,-41.7699041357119));
#433=CARTESIAN_POINT('',(8.65086672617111,38.1,-41.4501657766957));
#434=CARTESIAN_POINT('',(8.71206750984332,38.1,-41.2883433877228));
#435=CARTESIAN_POINT('',(8.82553928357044,38.1,-40.9608880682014));
#436=CARTESIAN_POINT('',(8.8777742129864,38.1,-40.7952426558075));
#437=CARTESIAN_POINT('',(8.97310305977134,38.1,-40.4608100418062));
#438=CARTESIAN_POINT('',(9.01616930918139,38.1,-40.2920149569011));
#439=CARTESIAN_POINT('',(9.09294930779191,38.1,-39.9519538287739));
#440=CARTESIAN_POINT('',(9.12664406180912,38.1,-39.7806834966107));
#441=CARTESIAN_POINT('',(9.18446323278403,38.1,-39.4363432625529));
#442=CARTESIAN_POINT('',(9.20857722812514,38.1,-39.2632716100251));
#443=CARTESIAN_POINT('',(9.24704086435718,38.1,-38.9160018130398));
#444=CARTESIAN_POINT('',(9.26138819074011,38.1,-38.7418034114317));
#445=CARTESIAN_POINT('',(9.2800358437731,38.1,-38.3929520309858));
#446=CARTESIAN_POINT('',(9.28434106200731,38.1,-38.2182993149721));
#447=CARTESIAN_POINT('',(9.28295576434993,38.1,-37.8693842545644));
#448=CARTESIAN_POINT('',(9.27728503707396,38.1,-37.6951218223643));
#449=CARTESIAN_POINT('',(9.25628384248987,38.1,-37.347618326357));
#450=CARTESIAN_POINT('',(9.24097751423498,38.1,-37.1743757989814));
#451=CARTESIAN_POINT('',(9.20073529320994,38.1,-36.8292958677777));
#452=CARTESIAN_POINT('',(9.17581503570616,38.1,-36.6574566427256));
#453=CARTESIAN_POINT('',(9.11646257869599,38.1,-36.3155655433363));
#454=CARTESIAN_POINT('',(9.08203769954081,38.1,-36.1455123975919));
#455=CARTESIAN_POINT('',(9.00377277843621,38.1,-35.8075737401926));
#456=CARTESIAN_POINT('',(8.95993207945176,38.1,-35.6396883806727));
#457=CARTESIAN_POINT('',(8.86292613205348,38.1,-35.306469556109));
#458=CARTESIAN_POINT('',(8.80975247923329,38.1,-35.141138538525));
#459=CARTESIAN_POINT('',(8.69421473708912,38.1,-34.813393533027));
#460=CARTESIAN_POINT('',(8.63183473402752,38.1,-34.6509851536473));
#461=CARTESIAN_POINT('',(8.49801523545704,38.1,-34.3299178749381));
#462=CARTESIAN_POINT('',(8.42657462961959,38.1,-34.1712594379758));
#463=CARTESIAN_POINT('',(8.27490750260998,38.1,-33.8585138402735));
#464=CARTESIAN_POINT('',(8.19469525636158,38.1,-33.7044197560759));
#465=CARTESIAN_POINT('',(8.02580736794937,38.1,-33.4011403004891));
#466=CARTESIAN_POINT('',(7.93714006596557,38.1,-33.2519502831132));
#467=CARTESIAN_POINT('',(7.75161716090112,38.1,-32.958837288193));
#468=CARTESIAN_POINT('',(7.65476490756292,38.1,-32.8149121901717));
#469=CARTESIAN_POINT('',(7.45316325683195,38.1,-32.5326769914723));
#470=CARTESIAN_POINT('',(7.34841290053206,38.1,-32.3943675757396));
#471=CARTESIAN_POINT('',(7.13128401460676,38.1,-32.1237309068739));
#472=CARTESIAN_POINT('',(7.01890072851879,38.1,-31.9914074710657));
#473=CARTESIAN_POINT('',(6.78684360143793,38.1,-31.7330419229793));
#474=CARTESIAN_POINT('',(6.66716163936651,38.1,-31.6070071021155));
#475=CARTESIAN_POINT('',(6.42079118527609,38.1,-31.3619705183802));
#476=CARTESIAN_POINT('',(6.29410260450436,38.1,-31.2429688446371));
#477=CARTESIAN_POINT('',(6.03418797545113,38.1,-31.0126251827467));
#478=CARTESIAN_POINT('',(5.90096907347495,38.1,-30.9012751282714));
#479=CARTESIAN_POINT('',(5.6285276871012,38.1,-30.686374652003));
#480=CARTESIAN_POINT('',(5.48930917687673,38.1,-30.5828191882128));
#481=CARTESIAN_POINT('',(5.20533473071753,38.1,-30.3837185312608));
#482=CARTESIAN_POINT('',(5.06058082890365,38.1,-30.2881704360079));
#483=CARTESIAN_POINT('',(4.7660183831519,38.1,-30.1052773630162));
#484=CARTESIAN_POINT('',(4.61621075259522,38.1,-30.0179309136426));
#485=CARTESIAN_POINT('',(4.31201812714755,38.1,-29.8516397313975));
#486=CARTESIAN_POINT('',(4.15763346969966,38.1,-29.7726943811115));
#487=CARTESIAN_POINT('',(3.84476484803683,38.1,-29.6234032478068));
#488=CARTESIAN_POINT('',(3.6862809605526,38.1,-29.5530573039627));
#489=CARTESIAN_POINT('',(3.3656913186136,38.1,-29.4211636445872));
#490=CARTESIAN_POINT('',(3.20358552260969,38.1,-29.3596160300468));
#491=CARTESIAN_POINT('',(2.87622948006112,38.1,-29.2455176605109));
#492=CARTESIAN_POINT('',(2.71097909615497,38.1,-29.1929672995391));
#493=CARTESIAN_POINT('',(2.37781124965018,38.1,-29.097062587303));
#494=CARTESIAN_POINT('',(2.20989350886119,38.1,-29.0537092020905));
#495=CARTESIAN_POINT('',(1.87186841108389,38.1,-28.9763953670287));
#496=CARTESIAN_POINT('',(1.70176057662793,38.1,-28.9424370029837));
#497=CARTESIAN_POINT('',(1.35983265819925,38.1,-28.8841168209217));
#498=CARTESIAN_POINT('',(1.18801188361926,38.1,-28.8597590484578));
#499=CARTESIAN_POINT('',(0.84313597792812,38.1,-28.8208157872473));
#500=CARTESIAN_POINT('',(0.67008003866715,38.1,-28.8062374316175));
#501=CARTESIAN_POINT('',(0.323209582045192,38.1,-28.787128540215));
#502=CARTESIAN_POINT('',(0.149394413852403,38.1,-28.7826097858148));
#503=CARTESIAN_POINT('',(-0.198185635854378,38.1,-28.7835158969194));
#504=CARTESIAN_POINT('',(-0.371950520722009,38.1,-28.7889397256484));
#505=CARTESIAN_POINT('',(-0.718672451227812,38.1,-28.8094122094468));
#506=CARTESIAN_POINT('',(-0.891630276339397,38.1,-28.8244477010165));
#507=CARTESIAN_POINT('',(-1.23630315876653,38.1,-28.8641669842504));
#508=CARTESIAN_POINT('',(-1.40801906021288,38.1,-28.8888434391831));
#509=CARTESIAN_POINT('',(-1.74977561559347,38.1,-28.9477660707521));
#510=CARTESIAN_POINT('',(-1.91981650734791,38.1,-28.9820108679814));
#511=CARTESIAN_POINT('',(-2.25778915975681,38.1,-29.0600228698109));
#512=CARTESIAN_POINT('',(-2.42571983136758,38.1,-29.103794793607));
#513=CARTESIAN_POINT('',(-2.75904532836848,38.1,-29.2007904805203));
#514=CARTESIAN_POINT('',(-2.92443693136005,38.1,-29.2540253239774));
#515=CARTESIAN_POINT('',(-3.2522346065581,38.1,-29.3699373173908));
#516=CARTESIAN_POINT('',(-3.4146343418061,38.1,-29.4326323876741));
#517=CARTESIAN_POINT('',(-3.73561636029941,38.1,-29.567034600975));
#518=CARTESIAN_POINT('',(-3.89419943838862,38.1,-29.6387398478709));
#519=CARTESIAN_POINT('',(-4.20680534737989,38.1,-29.7906627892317));
#520=CARTESIAN_POINT('',(-4.36083739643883,38.1,-29.8708615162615));
#521=CARTESIAN_POINT('',(-4.66401007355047,38.1,-30.0396405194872));
#522=CARTESIAN_POINT('',(-4.8131560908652,38.1,-30.1282111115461));
#523=CARTESIAN_POINT('',(-5.10625236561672,38.1,-30.3135445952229));
#524=CARTESIAN_POINT('',(-5.25020301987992,38.1,-30.4103068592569));
#525=CARTESIAN_POINT('',(-5.53259842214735,38.1,-30.6118504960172));
#526=CARTESIAN_POINT('',(-5.67103742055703,38.1,-30.7166399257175));
#527=CARTESIAN_POINT('',(-5.94210247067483,38.1,-30.9340608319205));
#528=CARTESIAN_POINT('',(-6.07471542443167,38.1,-31.0467086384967));
#529=CARTESIAN_POINT('',(-6.33382155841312,38.1,-31.279671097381));
#530=CARTESIAN_POINT('',(-6.46029304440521,38.1,-31.4000098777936));
#531=CARTESIAN_POINT('',(-6.7062562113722,38.1,-31.6476181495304));
#532=CARTESIAN_POINT('',(-6.82574796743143,38.1,-31.7748875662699));
#533=CARTESIAN_POINT('',(-7.05697734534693,38.1,-32.0355330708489));
#534=CARTESIAN_POINT('',(-7.16873933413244,38.1,-32.1688875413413));
#535=CARTESIAN_POINT('',(-7.38435419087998,38.1,-32.4413789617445));
#536=CARTESIAN_POINT('',(-7.48822350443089,38.1,-32.5805028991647));
#537=CARTESIAN_POINT('',(-7.6878978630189,38.1,-32.8642106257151));
#538=CARTESIAN_POINT('',(-7.78371097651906,38.1,-33.0087887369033));
#539=CARTESIAN_POINT('',(-7.9671222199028,38.1,-33.3030817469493));
#540=CARTESIAN_POINT('',(-8.05471965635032,38.1,-33.4527970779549));
#541=CARTESIAN_POINT('',(-8.22153367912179,38.1,-33.7570493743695));
#542=CARTESIAN_POINT('',(-8.30074046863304,38.1,-33.9115917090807));
#543=CARTESIAN_POINT('',(-8.45066557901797,38.1,-34.2251590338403));
#544=CARTESIAN_POINT('',(-8.52136480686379,38.1,-34.3841931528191));
#545=CARTESIAN_POINT('',(-8.65375001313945,38.1,-34.7060126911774));
#546=CARTESIAN_POINT('',(-8.71543409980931,38.1,-34.8687988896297));
#547=CARTESIAN_POINT('',(-8.82932669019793,38.1,-35.1973021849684));
#548=CARTESIAN_POINT('',(-8.88155320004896,38.1,-35.3630130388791));
#549=CARTESIAN_POINT('',(-8.97653787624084,38.1,-35.6969128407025));
#550=CARTESIAN_POINT('',(-9.01930717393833,38.1,-35.865098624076));
#551=CARTESIAN_POINT('',(-9.09532503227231,38.1,-36.2035197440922));
#552=CARTESIAN_POINT('',(-9.12857833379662,38.1,-36.373754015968));
#553=CARTESIAN_POINT('',(-9.18552759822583,38.1,-36.7158383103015));
#554=CARTESIAN_POINT('',(-9.20922218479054,38.1,-36.887688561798));
#555=CARTESIAN_POINT('',(-9.24701121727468,38.1,-37.2325733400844));
#556=CARTESIAN_POINT('',(-9.26109833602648,38.1,-37.4056086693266));
#557=CARTESIAN_POINT('',(-9.27963682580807,38.1,-37.752432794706));
#558=CARTESIAN_POINT('',(-9.28407495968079,38.1,-37.9262222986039));
#559=CARTESIAN_POINT('',(-9.28366596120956,38.1,-38.1));
#560=B_SPLINE_CURVE_WITH_KNOTS('',3,(#334,#335,#336,#337,#338,#339,#340,#341,#342,#343,#344,
#345,#346,#347,#348,#349,#350,#351,#352,#353,#354,#355,#356,#357,#358,#359,#360,#361,#362,#363,
#364,#365,#366,#367,#368,#369,#370,#371,#372,#373,#374,#375,#376,#377,#378,#379,#380,#381,#382,
#383,#384,#385,#386,#387,#388,#389,#390,#391,#392,#393,#394,#395,#396,#397,#398,#399,#400,#401,
#402,#403,#404,#405,#406,#407,#408,#409,#410,#411,#412,#413,#414,#415,#416,#417,#418,#419,#420,
#421,#422,#423,#424,#425,#426,#427,#428,#429,#430,#431,#432,#433,#434,#435,#436,#437,#438,#439,
#440,#441,#442,#443,#444,#445,#446,#447,#448,#449,#450,#451,#452,#453,#454,#455,#456,#457,#458,
#459,#460,#461,#462,#463,#464,#465,#466,#467,#468,#469,#470,#471,#472,#473,#474,#475,#476,#477,
#478,#479,#480,#481,#482,#483,#484,#485,#486,#487,#488,#489,#490,#491,#492,#493,#494,#495,#496,
#497,#498,#499,#500,#501,#502,#503,#504,#505,#506,#507,#508,#509,#510,#511,#512,#513,#514,#515,
#516,#517,#518,#519,#520,#521,#522,#523,#524,#525,#526,#527,#528,#529,#530,#531,#532,#533,#534,
#535,#536,#537,#538,#539,#540,#541,#542,#543,#544,#545,#546,#547,#548,#549,#550,#551,#552,#553,
#554,#555,#556,#557,#558,#559),.UNSPECIFIED.,.F.,.F.,(4,2,2,2,2,2,2,2,2,2,2,2,2,2,2,2,2,2,2,2,2,
2,2,2,2,2,2,2,2,2,2,2,2,2,2,2,2,2,2,2,2,2,2,2,2,2,2,2,2,2,2,2,2,2,2,2,2,2,2,2,2,2,2,2,2,2,2,2,2,
2,2,2,2,2,2,2,2,2,2,2,2,2,2,2,2,2,2,2,2,2,2,2,2,2,2,2,2,2,2,2,2,2,2,2,2,2,2,2,2,2,2,2,4),(0.,
0.521332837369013,1.04207110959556,1.56243852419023,2.08258967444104,2.6026236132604,
3.1225975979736,3.64254091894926,4.16246876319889,4.68239608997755,5.2023515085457,
5.72239114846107,6.24261250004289,6.76316817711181,7.28427951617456,7.80540136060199,
8.3259596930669,8.84620501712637,9.36638875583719,9.88677380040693,10.4076450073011,
10.9293195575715,11.4509744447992,11.9718047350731,12.4921933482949,13.0125257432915,
13.5331978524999,14.0546239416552,14.5772443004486,15.0998204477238,15.6211530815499,
16.141745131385,16.662077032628,17.18261320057,17.7038086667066,18.2261157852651,
18.7484247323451,19.2696142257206,19.790082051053,20.3101944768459,20.8302950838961,
21.350713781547,21.8717759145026,22.3933349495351,22.9149296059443,23.4363602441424,
23.957385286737,24.4777411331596,24.9971620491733,25.5154001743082,26.0341487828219,
26.5549372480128,27.0772756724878,27.600665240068,28.1246225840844,28.6487040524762,
29.1725301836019,29.6953184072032,30.2168021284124,30.7374413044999,31.2576806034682,
31.7779562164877,32.2987027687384,32.8203602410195,33.3420817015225,33.8629664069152,
34.3833425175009,34.9035066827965,35.4237341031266,35.9442887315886,36.4654335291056,
36.9865849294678,37.5071782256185,38.0274318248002,38.5474960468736,39.0674667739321,
39.5873992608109,40.1073220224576,40.6272507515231,41.147202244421,41.6672083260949,
42.1873297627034,42.7076701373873,43.2283896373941,43.7497186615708,44.2709933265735,
44.7915556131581,45.3117225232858,45.8318144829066,46.352164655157,46.87312817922,
47.3950912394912,47.9169446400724,48.4376562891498,48.9577728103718,49.4778495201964,
49.9984552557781,50.5201770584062,51.0436246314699,51.5670665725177,52.088775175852,
52.6093650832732,53.1294272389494,53.6495332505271,54.1702399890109,54.692094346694,
55.2140580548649,55.7350173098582,56.2553600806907,56.7754431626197,57.2956011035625,
57.8161553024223,58.337423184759),.UNSPECIFIED.);
#561=CARTESIAN_POINT('',(-9.28366596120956,38.1,-38.1));
#562=VERTEX_POINT('',#561);
#563=EDGE_CURVE('E58',#562,#562,#560,.F.);
#564=ORIENTED_EDGE('',*,*,#563,.T.);
#565=EDGE_LOOP('',(#564));
#566=FACE_BOUND('',#565,.T.);
#567=ORIENTED_EDGE('',*,*,#31,.F.);
#568=EDGE_LOOP('',(#567));
#569=FACE_BOUND('',#568,.T.);
#570=ADVANCED_FACE('F79',(#566,#569),#333,.T.);
#571=CARTESIAN_POINT('',(0.,0.,0.));
#572=DIRECTION('',(0.,0.,-1.));
#573=DIRECTION('',(-1.,0.,0.));
#574=AXIS2_PLACEMENT_3D('',#571,#572,#573);
#575=PLANE('',#574);
#576=CARTESIAN_POINT('',(-9.28366596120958,0.,0.));
#577=CARTESIAN_POINT('',(-9.29152283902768,2.43709941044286,0.));
#578=CARTESIAN_POINT('',(-8.30078094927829,4.84497820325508,0.));
#579=CARTESIAN_POINT('',(-5.73145559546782,7.43480440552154,0.));
#580=CARTESIAN_POINT('',(-4.70785747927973,8.12693984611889,0.));
#581=CARTESIAN_POINT('',(-2.46205270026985,9.06516735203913,0.));
#582=CARTESIAN_POINT('',(-1.25327513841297,9.31283352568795,0.));
#583=CARTESIAN_POINT('',(1.18717312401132,9.32098717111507,0.));
#584=CARTESIAN_POINT('',(2.39528461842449,9.0840792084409,0.));
#585=CARTESIAN_POINT('',(4.65650787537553,8.15705188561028,0.));
#586=CARTESIAN_POINT('',(5.67968863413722,7.47448661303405,0.));
#587=CARTESIAN_POINT('',(7.40803936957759,5.75675939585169,0.));
#588=CARTESIAN_POINT('',(8.0984166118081,4.72549518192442,0.));
#589=CARTESIAN_POINT('',(9.03053857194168,2.4957427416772,0.));
#590=CARTESIAN_POINT('',(9.28179445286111,1.27289519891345,0.));
#591=CARTESIAN_POINT('',(9.28554074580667,-1.17349505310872,0.));
#592=CARTESIAN_POINT('',(9.04865535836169,-2.37919637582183,0.));
#593=CARTESIAN_POINT('',(8.12293432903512,-4.63768193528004,0.));
#594=CARTESIAN_POINT('',(7.44000569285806,-5.66194701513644,0.));
#595=CARTESIAN_POINT('',(4.86458220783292,-8.25438794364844,0.));
#596=CARTESIAN_POINT('',(2.46103620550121,-9.25659443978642,0.));
#597=CARTESIAN_POINT('',(-1.18871180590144,-9.26685210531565,0.));
#598=CARTESIAN_POINT('',(-2.40046672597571,-9.03138050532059,0.));
#599=CARTESIAN_POINT('',(-4.65258259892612,-8.10321244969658,0.));
#600=CARTESIAN_POINT('',(-5.68045025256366,-7.42281834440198,0.));
#601=CARTESIAN_POINT('',(-7.4114413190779,-5.70055721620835,0.));
#602=CARTESIAN_POINT('',(-8.09689313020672,-4.67817521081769,0.));
#603=CARTESIAN_POINT('',(-9.0390138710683,-2.42488815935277,0.));
#604=CARTESIAN_POINT('',(-9.27973752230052,-1.21854970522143,0.));
#605=CARTESIAN_POINT('',(-9.28366596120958,0.,0.));
#606=B_SPLINE_CURVE_WITH_KNOTS('',3,(#576,#577,#578,#579,#580,#581,#582,#583,#584,#585,#586,
#587,#588,#589,#590,#591,#592,#593,#594,#595,#596,#597,#598,#599,#600,#601,#602,#603,#604,#605),
.UNSPECIFIED.,.T.,.F.,(4,2,2,2,2,2,2,2,2,2,2,2,2,2,4),(0.000922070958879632,0.00818004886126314,
0.0118090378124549,0.0154380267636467,0.0190670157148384,0.0226960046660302,0.0263249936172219,
0.0299539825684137,0.0335829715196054,0.0372119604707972,0.0444699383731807,0.0480989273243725,
0.0517279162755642,0.055356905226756,0.0589858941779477),.UNSPECIFIED.);
#607=CARTESIAN_POINT('',(-9.28366596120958,0.,0.));
#608=VERTEX_POINT('',#607);
#609=EDGE_CURVE('E11',#608,#608,#606,.F.);
#610=ORIENTED_EDGE('',*,*,#609,.T.);
#611=EDGE_LOOP('',(#610));
#612=FACE_BOUND('',#611,.T.);
#613=ORIENTED_EDGE('',*,*,#39,.T.);
#614=EDGE_LOOP('',(#613));
#615=FACE_BOUND('',#614,.T.);
#616=ADVANCED_FACE('F89',(#612,#615),#575,.F.);
#617=CARTESIAN_POINT('',(-9.28366596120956,38.1,-38.1));
#618=CARTESIAN_POINT('',(-9.28650207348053,38.1,-36.8824724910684));
#619=CARTESIAN_POINT('',(-9.05179334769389,38.1,-35.6728472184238));
#620=CARTESIAN_POINT('',(-8.12330760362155,38.1,-33.4173249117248));
#621=CARTESIAN_POINT('',(-7.44591304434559,38.1,-32.3922256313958));
#622=CARTESIAN_POINT('',(-5.72063753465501,38.1,-30.6554037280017));
#623=CARTESIAN_POINT('',(-4.69995893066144,38.1,-29.9711522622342));
#624=CARTESIAN_POINT('',(-2.45032549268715,38.1,-29.0285288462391));
#625=CARTESIAN_POINT('',(-1.24194526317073,38.1,-28.7867112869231));
#626=CARTESIAN_POINT('',(2.41067651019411,38.1,-28.7757660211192));
#627=CARTESIAN_POINT('',(4.81876480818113,38.1,-29.7673454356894));
#628=CARTESIAN_POINT('',(7.40658338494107,38.1,-32.3430616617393));
#629=CARTESIAN_POINT('',(8.09626064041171,38.1,-33.3654057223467));
#630=CARTESIAN_POINT('',(9.0335975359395,38.1,-35.6155169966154));
#631=CARTESIAN_POINT('',(9.27837935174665,38.1,-36.8217894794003));
#632=CARTESIAN_POINT('',(9.2889161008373,38.1,-39.2655480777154));
#633=CARTESIAN_POINT('',(9.04439150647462,38.1,-40.4930121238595));
#634=CARTESIAN_POINT('',(8.12582106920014,38.1,-42.7272151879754));
#635=CARTESIAN_POINT('',(7.43979981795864,38.1,-43.7634193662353));
#636=CARTESIAN_POINT('',(5.72314909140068,38.1,-45.4888827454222));
#637=CARTESIAN_POINT('',(4.70178945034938,38.1,-46.1782103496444));
#638=CARTESIAN_POINT('',(2.4481695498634,38.1,-47.1162494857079));
#639=CARTESIAN_POINT('',(1.2418050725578,38.1,-47.3608342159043));
#640=CARTESIAN_POINT('',(-1.2009201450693,38.1,-47.3660702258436));
#641=CARTESIAN_POINT('',(-2.4092003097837,38.1,-47.1263719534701));
#642=CARTESIAN_POINT('',(-4.6635569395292,38.1,-46.2001113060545));
#643=CARTESIAN_POINT('',(-5.68926547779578,38.1,-45.5149460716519));
#644=CARTESIAN_POINT('',(-8.27600511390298,38.1,-42.938544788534));
#645=CARTESIAN_POINT('',(-9.27799373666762,38.1,-40.5350550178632));
#646=CARTESIAN_POINT('',(-9.28366596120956,38.1,-38.1));
#647=CARTESIAN_POINT('',(-10.6679608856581,36.7155638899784,-38.1037461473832));
#648=CARTESIAN_POINT('',(-10.6712198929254,36.7221295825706,-36.7049100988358));
#649=CARTESIAN_POINT('',(-10.4015135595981,36.7293412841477,-35.3151911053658));
#650=CARTESIAN_POINT('',(-9.33458055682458,36.744176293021,-32.7239405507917));
#651=CARTESIAN_POINT('',(-8.55617914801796,36.751665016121,-31.5463033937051));
#652=CARTESIAN_POINT('',(-6.57364641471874,36.7653747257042,-29.5511046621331));
#653=CARTESIAN_POINT('',(-5.40077360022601,36.7713347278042,-28.7650983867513));
#654=CARTESIAN_POINT('',(-2.81569550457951,36.7798319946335,-27.6823186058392));
#655=CARTESIAN_POINT('',(-1.4271327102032,36.7821687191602,-27.4045568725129));
#656=CARTESIAN_POINT('',(2.7701344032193,36.7822619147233,-27.391983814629));
#657=CARTESIAN_POINT('',(5.53729471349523,36.7724846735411,-28.5309414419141));
#658=CARTESIAN_POINT('',(8.51098501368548,36.7520035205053,-31.4898224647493));
#659=CARTESIAN_POINT('',(9.30350059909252,36.7445339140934,-32.6642943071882));
#660=CARTESIAN_POINT('',(10.380604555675,36.7297030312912,-35.2493265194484));
#661=CARTESIAN_POINT('',(10.661885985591,36.7224962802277,-36.6351928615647));
#662=CARTESIAN_POINT('',(10.6739938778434,36.7092415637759,-39.4428599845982));
#663=CARTESIAN_POINT('',(10.3930080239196,36.7032472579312,-40.8531458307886));
#664=CARTESIAN_POINT('',(9.33746880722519,36.6931186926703,-43.4201557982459));
#665=CARTESIAN_POINT('',(8.54915437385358,36.6888252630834,-44.6107330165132));
#666=CARTESIAN_POINT('',(6.57653247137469,36.6820330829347,-46.5932710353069));
#667=CARTESIAN_POINT('',(5.40287707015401,36.6794966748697,-47.3853089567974));
#668=CARTESIAN_POINT('',(2.81321808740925,36.6761119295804,-48.4631194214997));
#669=CARTESIAN_POINT('',(1.42697162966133,36.6752664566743,-48.7441498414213));
#670=CARTESIAN_POINT('',(-1.37999031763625,36.6752499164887,-48.750166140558));
#671=CARTESIAN_POINT('',(-2.76843811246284,36.6760766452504,-48.4747502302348));
#672=CARTESIAN_POINT('',(-5.35894367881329,36.6794164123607,-47.4104731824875));
#673=CARTESIAN_POINT('',(-6.53759644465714,36.6819400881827,-46.6232179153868));
#674=CARTESIAN_POINT('',(-9.5100469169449,36.692052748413,-43.6629605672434));
#675=CARTESIAN_POINT('',(-10.6614428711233,36.7024325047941,-40.9014182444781));
#676=CARTESIAN_POINT('',(-10.6679608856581,36.7155638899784,-38.1037461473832));
#677=B_SPLINE_SURFACE_WITH_KNOTS('',1,3,((#617,#618,#619,#620,#621,#622,#623,#624,#625,#626,
#627,#628,#629,#630,#631,#632,#633,#634,#635,#636,#637,#638,#639,#640,#641,#642,#643,#644,#645,
#646),(#647,#648,#649,#650,#651,#652,#653,#654,#655,#656,#657,#658,#659,#660,#661,#662,#663,
#664,#665,#666,#667,#668,#669,#670,#671,#672,#673,#674,#675,#676)),.UNSPECIFIED.,.F.,.T.,.F.,(2,
2),(4,2,2,2,2,2,2,2,2,2,2,2,2,2,4),(0.,1.),(-0.0570412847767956,-0.0534123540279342,
-0.0497834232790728,-0.0461544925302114,-0.04252556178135,-0.0352677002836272,
-0.0316387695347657,-0.0280098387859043,-0.0243809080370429,-0.0207519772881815,
-0.0171230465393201,-0.0134941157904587,-0.00986518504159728,-0.00623625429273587,
0.00102160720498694),.UNSPECIFIED.);
#678=ORIENTED_EDGE('',*,*,#91,.F.);
#679=EDGE_LOOP('',(#678));
#680=FACE_BOUND('',#679,.T.);
#681=ORIENTED_EDGE('',*,*,#563,.F.);
#682=EDGE_LOOP('',(#681));
#683=FACE_BOUND('',#682,.T.);
#684=ADVANCED_FACE('F96',(#680,#683),#677,.T.);
#685=CARTESIAN_POINT('',(-10.6679608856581,-0.00374614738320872,-1.38443611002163));
#686=CARTESIAN_POINT('',(-10.67698930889,2.79627480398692,-1.37129322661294));
#687=CARTESIAN_POINT('',(-9.53851710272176,5.56255069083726,-1.35520319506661));
#688=CARTESIAN_POINT('',(-6.58607756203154,8.53764509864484,-1.33467370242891));
#689=CARTESIAN_POINT('',(-5.4098499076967,9.33271014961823,-1.3286840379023));
#690=CARTESIAN_POINT('',(-2.82917136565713,10.4104401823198,-1.32022319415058));
#691=CARTESIAN_POINT('',(-1.44015200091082,10.6949202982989,-1.31783596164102));
#692=CARTESIAN_POINT('',(1.36419346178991,10.7042864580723,-1.31776497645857));
#693=CARTESIAN_POINT('',(2.75244744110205,10.4321635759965,-1.3200467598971));
#694=CARTESIAN_POINT('',(5.35084352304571,9.36729990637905,-1.32841865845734));
#695=CARTESIAN_POINT('',(6.52659158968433,8.58323021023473,-1.334356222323));
#696=CARTESIAN_POINT('',(8.51265809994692,6.60997088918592,-1.34798085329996));
#697=CARTESIAN_POINT('',(9.30597804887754,5.42525194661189,-1.35552126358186));
#698=CARTESIAN_POINT('',(10.3770894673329,2.86360947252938,-1.3702275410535));
#699=CARTESIAN_POINT('',(10.6658103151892,1.45870076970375,-1.37754122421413));
#700=CARTESIAN_POINT('',(10.6701152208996,-1.35199084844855,-1.39079284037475));
#701=CARTESIAN_POINT('',(10.3979076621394,-2.73727223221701,-1.39668728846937));
#702=CARTESIAN_POINT('',(9.33415162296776,-5.33218152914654,-1.40693157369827));
#703=CARTESIAN_POINT('',(8.54939094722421,-6.50904120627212,-1.41117219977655));
#704=CARTESIAN_POINT('',(5.58994398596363,-9.48772696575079,-1.42136740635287));
#705=CARTESIAN_POINT('',(2.82800330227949,-10.6392782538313,-1.42471981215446));
#706=CARTESIAN_POINT('',(-1.36596158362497,-10.6510645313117,-1.42475271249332));
#707=CARTESIAN_POINT('',(-2.75840225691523,-10.380505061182,-1.42394173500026));
#708=CARTESIAN_POINT('',(-5.34633294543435,-9.31403642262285,-1.42059445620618));
#709=CARTESIAN_POINT('',(-6.52746677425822,-8.53226287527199,-1.41809584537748));
#710=CARTESIAN_POINT('',(-8.51656731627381,-6.55340376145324,-1.41132584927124));
#711=CARTESIAN_POINT('',(-9.30422739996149,-5.378707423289,-1.40710033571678));
#712=CARTESIAN_POINT('',(-10.3868285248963,-2.78976953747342,-1.39690897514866));
#713=CARTESIAN_POINT('',(-10.6634466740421,-1.40375662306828,-1.39100755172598));
#714=CARTESIAN_POINT('',(-10.6679608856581,-0.00374614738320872,-1.38443611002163));
#715=CARTESIAN_POINT('',(-9.28366596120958,0.,0.));
#716=CARTESIAN_POINT('',(-9.29152283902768,2.43709941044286,0.));
#717=CARTESIAN_POINT('',(-8.30078094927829,4.84497820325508,0.));
#718=CARTESIAN_POINT('',(-5.73145559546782,7.43480440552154,0.));
#719=CARTESIAN_POINT('',(-4.70785747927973,8.12693984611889,0.));
#720=CARTESIAN_POINT('',(-2.46205270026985,9.06516735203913,0.));
#721=CARTESIAN_POINT('',(-1.25327513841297,9.31283352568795,0.));
#722=CARTESIAN_POINT('',(1.18717312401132,9.32098717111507,0.));
#723=CARTESIAN_POINT('',(2.39528461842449,9.0840792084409,0.));
#724=CARTESIAN_POINT('',(4.65650787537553,8.15705188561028,0.));
#725=CARTESIAN_POINT('',(5.67968863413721,7.47448661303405,0.));
#726=CARTESIAN_POINT('',(7.40803936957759,5.75675939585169,0.));
#727=CARTESIAN_POINT('',(8.0984166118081,4.72549518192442,0.));
#728=CARTESIAN_POINT('',(9.03053857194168,2.4957427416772,0.));
#729=CARTESIAN_POINT('',(9.28179445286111,1.27289519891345,0.));
#730=CARTESIAN_POINT('',(9.28554074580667,-1.17349505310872,0.));
#731=CARTESIAN_POINT('',(9.04865535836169,-2.37919637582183,0.));
#732=CARTESIAN_POINT('',(8.12293432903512,-4.63768193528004,0.));
#733=CARTESIAN_POINT('',(7.44000569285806,-5.66194701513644,0.));
#734=CARTESIAN_POINT('',(4.86458220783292,-8.25438794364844,0.));
#735=CARTESIAN_POINT('',(2.46103620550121,-9.25659443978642,0.));
#736=CARTESIAN_POINT('',(-1.18871180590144,-9.26685210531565,0.));
#737=CARTESIAN_POINT('',(-2.40046672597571,-9.03138050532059,0.));
#738=CARTESIAN_POINT('',(-4.65258259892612,-8.10321244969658,0.));
#739=CARTESIAN_POINT('',(-5.68045025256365,-7.42281834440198,0.));
#740=CARTESIAN_POINT('',(-7.4114413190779,-5.70055721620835,0.));
#741=CARTESIAN_POINT('',(-8.09689313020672,-4.67817521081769,0.));
#742=CARTESIAN_POINT('',(-9.0390138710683,-2.42488815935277,0.));
#743=CARTESIAN_POINT('',(-9.27973752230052,-1.21854970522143,0.));
#744=CARTESIAN_POINT('',(-9.28366596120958,0.,0.));
#745=B_SPLINE_SURFACE_WITH_KNOTS('',1,3,((#685,#686,#687,#688,#689,#690,#691,#692,#693,#694,
#695,#696,#697,#698,#699,#700,#701,#702,#703,#704,#705,#706,#707,#708,#709,#710,#711,#712,#713,
#714),(#715,#716,#717,#718,#719,#720,#721,#722,#723,#724,#725,#726,#727,#728,#729,#730,#731,
#732,#733,#734,#735,#736,#737,#738,#739,#740,#741,#742,#743,#744)),.UNSPECIFIED.,.F.,.T.,.F.,(2,
2),(4,2,2,2,2,2,2,2,2,2,2,2,2,2,4),(0.,1.),(0.000922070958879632,0.00818004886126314,
0.0118090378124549,0.0154380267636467,0.0190670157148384,0.0226960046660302,0.0263249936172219,
0.0299539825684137,0.0335829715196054,0.0372119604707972,0.0444699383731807,0.0480989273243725,
0.0517279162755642,0.055356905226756,0.0589858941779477),.UNSPECIFIED.);
#746=ORIENTED_EDGE('',*,*,#609,.F.);
#747=EDGE_LOOP('',(#746));
#748=FACE_BOUND('',#747,.T.);
#749=ORIENTED_EDGE('',*,*,#324,.F.);
#750=EDGE_LOOP('',(#749));
#751=FACE_BOUND('',#750,.T.);
#752=ADVANCED_FACE('F38',(#748,#751),#745,.T.);
#753=CLOSED_SHELL('',(#52,#328,#570,#616,#684,#752));
#754=MANIFOLD_SOLID_BREP('B2',#753);
#755=ADVANCED_BREP_SHAPE_REPRESENTATION('',(#18,#754),#14);
#756=SHAPE_DEFINITION_REPRESENTATION(#9,#755);
ENDSEC;
END-ISO-10303-21;
